VERSION 5.8 ;
BUSBITCHARS "[]" ;
DIVIDERCHAR "/" ;
UNITS
    DATABASE MICRONS 2000 ;
END UNITS

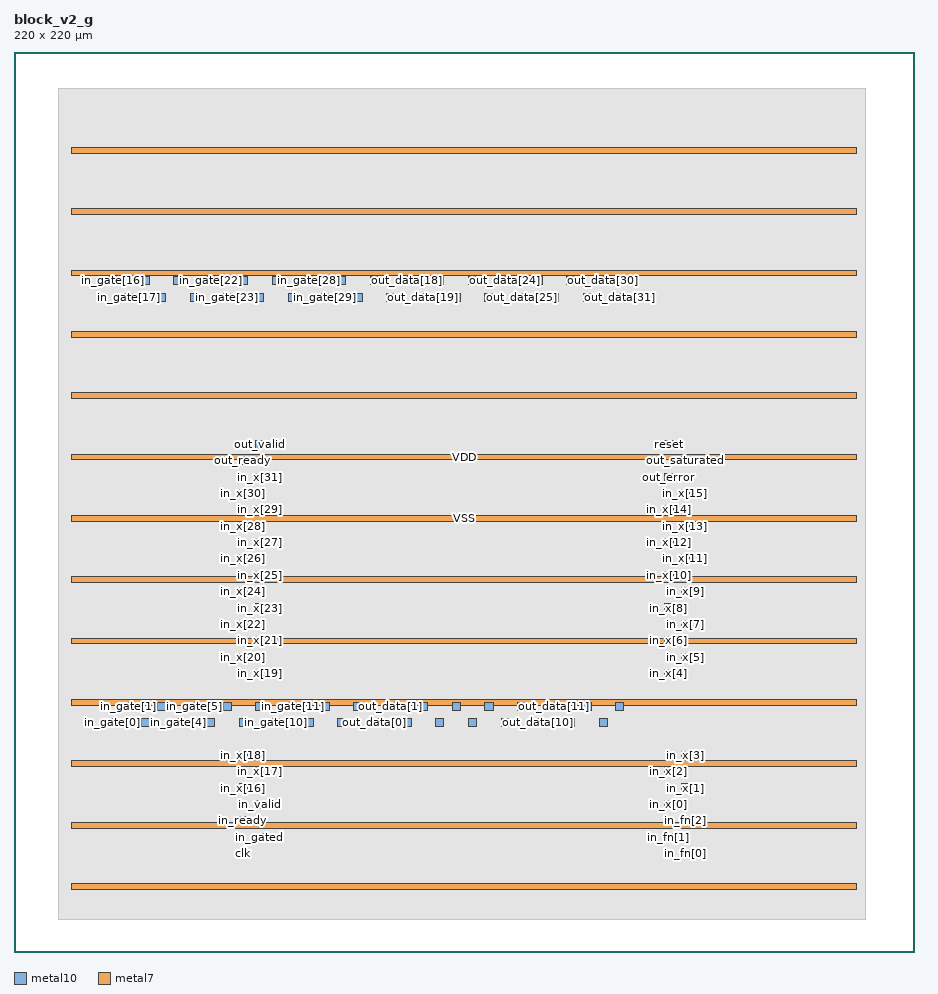
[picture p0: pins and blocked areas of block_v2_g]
MACRO block_v2_g
  FOREIGN block_v2_g 0 0 ;
  CLASS BLOCK ;
  SIZE 220 BY 220 ;
  PIN clk
    DIRECTION INPUT ;
    USE SIGNAL ;
    PORT
      LAYER metal10 ;
        RECT  55.095 23.07 57.095 25.07 ;
    END
  END clk
  PIN in_fn[0]
    DIRECTION INPUT ;
    USE SIGNAL ;
    PORT
      LAYER metal10 ;
        RECT  163.095 23.07 165.095 25.07 ;
    END
  END in_fn[0]
  PIN in_fn[1]
    DIRECTION INPUT ;
    USE SIGNAL ;
    PORT
      LAYER metal10 ;
        RECT  159.095 27.07 161.095 29.07 ;
    END
  END in_fn[1]
  PIN in_fn[2]
    DIRECTION INPUT ;
    USE SIGNAL ;
    PORT
      LAYER metal10 ;
        RECT  163.095 31.07 165.095 33.07 ;
    END
  END in_fn[2]
  PIN in_gate[0]
    DIRECTION INPUT ;
    USE SIGNAL ;
    PORT
      LAYER metal10 ;
        RECT  23.095 55.07 25.095 57.07 ;
    END
  END in_gate[0]
  PIN in_gate[10]
    DIRECTION INPUT ;
    USE SIGNAL ;
    PORT
      LAYER metal10 ;
        RECT  63.095 55.07 65.095 57.07 ;
    END
  END in_gate[10]
  PIN in_gate[11]
    DIRECTION INPUT ;
    USE SIGNAL ;
    PORT
      LAYER metal10 ;
        RECT  67.095 59.07 69.095 61.07 ;
    END
  END in_gate[11]
  PIN in_gate[12]
    DIRECTION INPUT ;
    USE SIGNAL ;
    PORT
      LAYER metal10 ;
        RECT  71.095 55.07 73.095 57.07 ;
    END
  END in_gate[12]
  PIN in_gate[13]
    DIRECTION INPUT ;
    USE SIGNAL ;
    PORT
      LAYER metal10 ;
        RECT  75.095 59.07 77.095 61.07 ;
    END
  END in_gate[13]
  PIN in_gate[14]
    DIRECTION INPUT ;
    USE SIGNAL ;
    PORT
      LAYER metal10 ;
        RECT  79.095 55.07 81.095 57.07 ;
    END
  END in_gate[14]
  PIN in_gate[15]
    DIRECTION INPUT ;
    USE SIGNAL ;
    PORT
      LAYER metal10 ;
        RECT  83.095 59.07 85.095 61.07 ;
    END
  END in_gate[15]
  PIN in_gate[16]
    DIRECTION INPUT ;
    USE SIGNAL ;
    PORT
      LAYER metal10 ;
        RECT  23.095 163.07 25.095 165.07 ;
    END
  END in_gate[16]
  PIN in_gate[17]
    DIRECTION INPUT ;
    USE SIGNAL ;
    PORT
      LAYER metal10 ;
        RECT  27.095 159.07 29.095 161.07 ;
    END
  END in_gate[17]
  PIN in_gate[18]
    DIRECTION INPUT ;
    USE SIGNAL ;
    PORT
      LAYER metal10 ;
        RECT  31.095 163.07 33.095 165.07 ;
    END
  END in_gate[18]
  PIN in_gate[19]
    DIRECTION INPUT ;
    USE SIGNAL ;
    PORT
      LAYER metal10 ;
        RECT  35.095 159.07 37.095 161.07 ;
    END
  END in_gate[19]
  PIN in_gate[1]
    DIRECTION INPUT ;
    USE SIGNAL ;
    PORT
      LAYER metal10 ;
        RECT  27.095 59.07 29.095 61.07 ;
    END
  END in_gate[1]
  PIN in_gate[20]
    DIRECTION INPUT ;
    USE SIGNAL ;
    PORT
      LAYER metal10 ;
        RECT  39.095 163.07 41.095 165.07 ;
    END
  END in_gate[20]
  PIN in_gate[21]
    DIRECTION INPUT ;
    USE SIGNAL ;
    PORT
      LAYER metal10 ;
        RECT  43.095 159.07 45.095 161.07 ;
    END
  END in_gate[21]
  PIN in_gate[22]
    DIRECTION INPUT ;
    USE SIGNAL ;
    PORT
      LAYER metal10 ;
        RECT  47.095 163.07 49.095 165.07 ;
    END
  END in_gate[22]
  PIN in_gate[23]
    DIRECTION INPUT ;
    USE SIGNAL ;
    PORT
      LAYER metal10 ;
        RECT  51.095 159.07 53.095 161.07 ;
    END
  END in_gate[23]
  PIN in_gate[24]
    DIRECTION INPUT ;
    USE SIGNAL ;
    PORT
      LAYER metal10 ;
        RECT  55.095 163.07 57.095 165.07 ;
    END
  END in_gate[24]
  PIN in_gate[25]
    DIRECTION INPUT ;
    USE SIGNAL ;
    PORT
      LAYER metal10 ;
        RECT  59.095 159.07 61.095 161.07 ;
    END
  END in_gate[25]
  PIN in_gate[26]
    DIRECTION INPUT ;
    USE SIGNAL ;
    PORT
      LAYER metal10 ;
        RECT  63.095 163.07 65.095 165.07 ;
    END
  END in_gate[26]
  PIN in_gate[27]
    DIRECTION INPUT ;
    USE SIGNAL ;
    PORT
      LAYER metal10 ;
        RECT  67.095 159.07 69.095 161.07 ;
    END
  END in_gate[27]
  PIN in_gate[28]
    DIRECTION INPUT ;
    USE SIGNAL ;
    PORT
      LAYER metal10 ;
        RECT  71.095 163.07 73.095 165.07 ;
    END
  END in_gate[28]
  PIN in_gate[29]
    DIRECTION INPUT ;
    USE SIGNAL ;
    PORT
      LAYER metal10 ;
        RECT  75.095 159.07 77.095 161.07 ;
    END
  END in_gate[29]
  PIN in_gate[2]
    DIRECTION INPUT ;
    USE SIGNAL ;
    PORT
      LAYER metal10 ;
        RECT  31.095 55.07 33.095 57.07 ;
    END
  END in_gate[2]
  PIN in_gate[30]
    DIRECTION INPUT ;
    USE SIGNAL ;
    PORT
      LAYER metal10 ;
        RECT  79.095 163.07 81.095 165.07 ;
    END
  END in_gate[30]
  PIN in_gate[31]
    DIRECTION INPUT ;
    USE SIGNAL ;
    PORT
      LAYER metal10 ;
        RECT  83.095 159.07 85.095 161.07 ;
    END
  END in_gate[31]
  PIN in_gate[3]
    DIRECTION INPUT ;
    USE SIGNAL ;
    PORT
      LAYER metal10 ;
        RECT  35.095 59.07 37.095 61.07 ;
    END
  END in_gate[3]
  PIN in_gate[4]
    DIRECTION INPUT ;
    USE SIGNAL ;
    PORT
      LAYER metal10 ;
        RECT  39.095 55.07 41.095 57.07 ;
    END
  END in_gate[4]
  PIN in_gate[5]
    DIRECTION INPUT ;
    USE SIGNAL ;
    PORT
      LAYER metal10 ;
        RECT  43.095 59.07 45.095 61.07 ;
    END
  END in_gate[5]
  PIN in_gate[6]
    DIRECTION INPUT ;
    USE SIGNAL ;
    PORT
      LAYER metal10 ;
        RECT  47.095 55.07 49.095 57.07 ;
    END
  END in_gate[6]
  PIN in_gate[7]
    DIRECTION INPUT ;
    USE SIGNAL ;
    PORT
      LAYER metal10 ;
        RECT  51.095 59.07 53.095 61.07 ;
    END
  END in_gate[7]
  PIN in_gate[8]
    DIRECTION INPUT ;
    USE SIGNAL ;
    PORT
      LAYER metal10 ;
        RECT  55.095 55.07 57.095 57.07 ;
    END
  END in_gate[8]
  PIN in_gate[9]
    DIRECTION INPUT ;
    USE SIGNAL ;
    PORT
      LAYER metal10 ;
        RECT  59.095 59.07 61.095 61.07 ;
    END
  END in_gate[9]
  PIN in_gated
    DIRECTION INPUT ;
    USE SIGNAL ;
    PORT
      LAYER metal10 ;
        RECT  59.095 27.07 61.095 29.07 ;
    END
  END in_gated
  PIN in_ready
    DIRECTION OUTPUT ;
    USE SIGNAL ;
    PORT
      LAYER metal10 ;
        RECT  55.095 31.07 57.095 33.07 ;
    END
  END in_ready
  PIN in_valid
    DIRECTION INPUT ;
    USE SIGNAL ;
    PORT
      LAYER metal10 ;
        RECT  59.095 35.07 61.095 37.07 ;
    END
  END in_valid
  PIN in_x[0]
    DIRECTION INPUT ;
    USE SIGNAL ;
    PORT
      LAYER metal10 ;
        RECT  159.095 35.07 161.095 37.07 ;
    END
  END in_x[0]
  PIN in_x[10]
    DIRECTION INPUT ;
    USE SIGNAL ;
    PORT
      LAYER metal10 ;
        RECT  159.095 91.07 161.095 93.07 ;
    END
  END in_x[10]
  PIN in_x[11]
    DIRECTION INPUT ;
    USE SIGNAL ;
    PORT
      LAYER metal10 ;
        RECT  163.095 95.07 165.095 97.07 ;
    END
  END in_x[11]
  PIN in_x[12]
    DIRECTION INPUT ;
    USE SIGNAL ;
    PORT
      LAYER metal10 ;
        RECT  159.095 99.07 161.095 101.07 ;
    END
  END in_x[12]
  PIN in_x[13]
    DIRECTION INPUT ;
    USE SIGNAL ;
    PORT
      LAYER metal10 ;
        RECT  163.095 103.07 165.095 105.07 ;
    END
  END in_x[13]
  PIN in_x[14]
    DIRECTION INPUT ;
    USE SIGNAL ;
    PORT
      LAYER metal10 ;
        RECT  159.095 107.07 161.095 109.07 ;
    END
  END in_x[14]
  PIN in_x[15]
    DIRECTION INPUT ;
    USE SIGNAL ;
    PORT
      LAYER metal10 ;
        RECT  163.095 111.07 165.095 113.07 ;
    END
  END in_x[15]
  PIN in_x[16]
    DIRECTION INPUT ;
    USE SIGNAL ;
    PORT
      LAYER metal10 ;
        RECT  55.095 39.07 57.095 41.07 ;
    END
  END in_x[16]
  PIN in_x[17]
    DIRECTION INPUT ;
    USE SIGNAL ;
    PORT
      LAYER metal10 ;
        RECT  59.095 43.07 61.095 45.07 ;
    END
  END in_x[17]
  PIN in_x[18]
    DIRECTION INPUT ;
    USE SIGNAL ;
    PORT
      LAYER metal10 ;
        RECT  55.095 47.07 57.095 49.07 ;
    END
  END in_x[18]
  PIN in_x[19]
    DIRECTION INPUT ;
    USE SIGNAL ;
    PORT
      LAYER metal10 ;
        RECT  59.095 67.07 61.095 69.07 ;
    END
  END in_x[19]
  PIN in_x[1]
    DIRECTION INPUT ;
    USE SIGNAL ;
    PORT
      LAYER metal10 ;
        RECT  163.095 39.07 165.095 41.07 ;
    END
  END in_x[1]
  PIN in_x[20]
    DIRECTION INPUT ;
    USE SIGNAL ;
    PORT
      LAYER metal10 ;
        RECT  55.095 71.07 57.095 73.07 ;
    END
  END in_x[20]
  PIN in_x[21]
    DIRECTION INPUT ;
    USE SIGNAL ;
    PORT
      LAYER metal10 ;
        RECT  59.095 75.07 61.095 77.07 ;
    END
  END in_x[21]
  PIN in_x[22]
    DIRECTION INPUT ;
    USE SIGNAL ;
    PORT
      LAYER metal10 ;
        RECT  55.095 79.07 57.095 81.07 ;
    END
  END in_x[22]
  PIN in_x[23]
    DIRECTION INPUT ;
    USE SIGNAL ;
    PORT
      LAYER metal10 ;
        RECT  59.095 83.07 61.095 85.07 ;
    END
  END in_x[23]
  PIN in_x[24]
    DIRECTION INPUT ;
    USE SIGNAL ;
    PORT
      LAYER metal10 ;
        RECT  55.095 87.07 57.095 89.07 ;
    END
  END in_x[24]
  PIN in_x[25]
    DIRECTION INPUT ;
    USE SIGNAL ;
    PORT
      LAYER metal10 ;
        RECT  59.095 91.07 61.095 93.07 ;
    END
  END in_x[25]
  PIN in_x[26]
    DIRECTION INPUT ;
    USE SIGNAL ;
    PORT
      LAYER metal10 ;
        RECT  55.095 95.07 57.095 97.07 ;
    END
  END in_x[26]
  PIN in_x[27]
    DIRECTION INPUT ;
    USE SIGNAL ;
    PORT
      LAYER metal10 ;
        RECT  59.095 99.07 61.095 101.07 ;
    END
  END in_x[27]
  PIN in_x[28]
    DIRECTION INPUT ;
    USE SIGNAL ;
    PORT
      LAYER metal10 ;
        RECT  55.095 103.07 57.095 105.07 ;
    END
  END in_x[28]
  PIN in_x[29]
    DIRECTION INPUT ;
    USE SIGNAL ;
    PORT
      LAYER metal10 ;
        RECT  59.095 107.07 61.095 109.07 ;
    END
  END in_x[29]
  PIN in_x[2]
    DIRECTION INPUT ;
    USE SIGNAL ;
    PORT
      LAYER metal10 ;
        RECT  159.095 43.07 161.095 45.07 ;
    END
  END in_x[2]
  PIN in_x[30]
    DIRECTION INPUT ;
    USE SIGNAL ;
    PORT
      LAYER metal10 ;
        RECT  55.095 111.07 57.095 113.07 ;
    END
  END in_x[30]
  PIN in_x[31]
    DIRECTION INPUT ;
    USE SIGNAL ;
    PORT
      LAYER metal10 ;
        RECT  59.095 115.07 61.095 117.07 ;
    END
  END in_x[31]
  PIN in_x[3]
    DIRECTION INPUT ;
    USE SIGNAL ;
    PORT
      LAYER metal10 ;
        RECT  163.095 47.07 165.095 49.07 ;
    END
  END in_x[3]
  PIN in_x[4]
    DIRECTION INPUT ;
    USE SIGNAL ;
    PORT
      LAYER metal10 ;
        RECT  159.095 67.07 161.095 69.07 ;
    END
  END in_x[4]
  PIN in_x[5]
    DIRECTION INPUT ;
    USE SIGNAL ;
    PORT
      LAYER metal10 ;
        RECT  163.095 71.07 165.095 73.07 ;
    END
  END in_x[5]
  PIN in_x[6]
    DIRECTION INPUT ;
    USE SIGNAL ;
    PORT
      LAYER metal10 ;
        RECT  159.095 75.07 161.095 77.07 ;
    END
  END in_x[6]
  PIN in_x[7]
    DIRECTION INPUT ;
    USE SIGNAL ;
    PORT
      LAYER metal10 ;
        RECT  163.095 79.07 165.095 81.07 ;
    END
  END in_x[7]
  PIN in_x[8]
    DIRECTION INPUT ;
    USE SIGNAL ;
    PORT
      LAYER metal10 ;
        RECT  159.095 83.07 161.095 85.07 ;
    END
  END in_x[8]
  PIN in_x[9]
    DIRECTION INPUT ;
    USE SIGNAL ;
    PORT
      LAYER metal10 ;
        RECT  163.095 87.07 165.095 89.07 ;
    END
  END in_x[9]
  PIN out_data[0]
    DIRECTION OUTPUT ;
    USE SIGNAL ;
    PORT
      LAYER metal10 ;
        RECT  87.095 55.07 89.095 57.07 ;
    END
  END out_data[0]
  PIN out_data[10]
    DIRECTION OUTPUT ;
    USE SIGNAL ;
    PORT
      LAYER metal10 ;
        RECT  127.095 55.07 129.095 57.07 ;
    END
  END out_data[10]
  PIN out_data[11]
    DIRECTION OUTPUT ;
    USE SIGNAL ;
    PORT
      LAYER metal10 ;
        RECT  131.095 59.07 133.095 61.07 ;
    END
  END out_data[11]
  PIN out_data[12]
    DIRECTION OUTPUT ;
    USE SIGNAL ;
    PORT
      LAYER metal10 ;
        RECT  135.095 55.07 137.095 57.07 ;
    END
  END out_data[12]
  PIN out_data[13]
    DIRECTION OUTPUT ;
    USE SIGNAL ;
    PORT
      LAYER metal10 ;
        RECT  139.095 59.07 141.095 61.07 ;
    END
  END out_data[13]
  PIN out_data[14]
    DIRECTION OUTPUT ;
    USE SIGNAL ;
    PORT
      LAYER metal10 ;
        RECT  143.095 55.07 145.095 57.07 ;
    END
  END out_data[14]
  PIN out_data[15]
    DIRECTION OUTPUT ;
    USE SIGNAL ;
    PORT
      LAYER metal10 ;
        RECT  147.095 59.07 149.095 61.07 ;
    END
  END out_data[15]
  PIN out_data[16]
    DIRECTION OUTPUT ;
    USE SIGNAL ;
    PORT
      LAYER metal10 ;
        RECT  87.095 163.07 89.095 165.07 ;
    END
  END out_data[16]
  PIN out_data[17]
    DIRECTION OUTPUT ;
    USE SIGNAL ;
    PORT
      LAYER metal10 ;
        RECT  91.095 159.07 93.095 161.07 ;
    END
  END out_data[17]
  PIN out_data[18]
    DIRECTION OUTPUT ;
    USE SIGNAL ;
    PORT
      LAYER metal10 ;
        RECT  95.095 163.07 97.095 165.07 ;
    END
  END out_data[18]
  PIN out_data[19]
    DIRECTION OUTPUT ;
    USE SIGNAL ;
    PORT
      LAYER metal10 ;
        RECT  99.095 159.07 101.095 161.07 ;
    END
  END out_data[19]
  PIN out_data[1]
    DIRECTION OUTPUT ;
    USE SIGNAL ;
    PORT
      LAYER metal10 ;
        RECT  91.095 59.07 93.095 61.07 ;
    END
  END out_data[1]
  PIN out_data[20]
    DIRECTION OUTPUT ;
    USE SIGNAL ;
    PORT
      LAYER metal10 ;
        RECT  103.095 163.07 105.095 165.07 ;
    END
  END out_data[20]
  PIN out_data[21]
    DIRECTION OUTPUT ;
    USE SIGNAL ;
    PORT
      LAYER metal10 ;
        RECT  107.095 159.07 109.095 161.07 ;
    END
  END out_data[21]
  PIN out_data[22]
    DIRECTION OUTPUT ;
    USE SIGNAL ;
    PORT
      LAYER metal10 ;
        RECT  111.095 163.07 113.095 165.07 ;
    END
  END out_data[22]
  PIN out_data[23]
    DIRECTION OUTPUT ;
    USE SIGNAL ;
    PORT
      LAYER metal10 ;
        RECT  115.095 159.07 117.095 161.07 ;
    END
  END out_data[23]
  PIN out_data[24]
    DIRECTION OUTPUT ;
    USE SIGNAL ;
    PORT
      LAYER metal10 ;
        RECT  119.095 163.07 121.095 165.07 ;
    END
  END out_data[24]
  PIN out_data[25]
    DIRECTION OUTPUT ;
    USE SIGNAL ;
    PORT
      LAYER metal10 ;
        RECT  123.095 159.07 125.095 161.07 ;
    END
  END out_data[25]
  PIN out_data[26]
    DIRECTION OUTPUT ;
    USE SIGNAL ;
    PORT
      LAYER metal10 ;
        RECT  127.095 163.07 129.095 165.07 ;
    END
  END out_data[26]
  PIN out_data[27]
    DIRECTION OUTPUT ;
    USE SIGNAL ;
    PORT
      LAYER metal10 ;
        RECT  131.095 159.07 133.095 161.07 ;
    END
  END out_data[27]
  PIN out_data[28]
    DIRECTION OUTPUT ;
    USE SIGNAL ;
    PORT
      LAYER metal10 ;
        RECT  135.095 163.07 137.095 165.07 ;
    END
  END out_data[28]
  PIN out_data[29]
    DIRECTION OUTPUT ;
    USE SIGNAL ;
    PORT
      LAYER metal10 ;
        RECT  139.095 159.07 141.095 161.07 ;
    END
  END out_data[29]
  PIN out_data[2]
    DIRECTION OUTPUT ;
    USE SIGNAL ;
    PORT
      LAYER metal10 ;
        RECT  95.095 55.07 97.095 57.07 ;
    END
  END out_data[2]
  PIN out_data[30]
    DIRECTION OUTPUT ;
    USE SIGNAL ;
    PORT
      LAYER metal10 ;
        RECT  143.095 163.07 145.095 165.07 ;
    END
  END out_data[30]
  PIN out_data[31]
    DIRECTION OUTPUT ;
    USE SIGNAL ;
    PORT
      LAYER metal10 ;
        RECT  147.095 159.07 149.095 161.07 ;
    END
  END out_data[31]
  PIN out_data[3]
    DIRECTION OUTPUT ;
    USE SIGNAL ;
    PORT
      LAYER metal10 ;
        RECT  99.095 59.07 101.095 61.07 ;
    END
  END out_data[3]
  PIN out_data[4]
    DIRECTION OUTPUT ;
    USE SIGNAL ;
    PORT
      LAYER metal10 ;
        RECT  103.095 55.07 105.095 57.07 ;
    END
  END out_data[4]
  PIN out_data[5]
    DIRECTION OUTPUT ;
    USE SIGNAL ;
    PORT
      LAYER metal10 ;
        RECT  107.095 59.07 109.095 61.07 ;
    END
  END out_data[5]
  PIN out_data[6]
    DIRECTION OUTPUT ;
    USE SIGNAL ;
    PORT
      LAYER metal10 ;
        RECT  111.095 55.07 113.095 57.07 ;
    END
  END out_data[6]
  PIN out_data[7]
    DIRECTION OUTPUT ;
    USE SIGNAL ;
    PORT
      LAYER metal10 ;
        RECT  115.095 59.07 117.095 61.07 ;
    END
  END out_data[7]
  PIN out_data[8]
    DIRECTION OUTPUT ;
    USE SIGNAL ;
    PORT
      LAYER metal10 ;
        RECT  119.095 55.07 121.095 57.07 ;
    END
  END out_data[8]
  PIN out_data[9]
    DIRECTION OUTPUT ;
    USE SIGNAL ;
    PORT
      LAYER metal10 ;
        RECT  123.095 59.07 125.095 61.07 ;
    END
  END out_data[9]
  PIN out_error
    DIRECTION OUTPUT ;
    USE SIGNAL ;
    PORT
      LAYER metal10 ;
        RECT  159.095 115.07 161.095 117.07 ;
    END
  END out_error
  PIN out_ready
    DIRECTION INPUT ;
    USE SIGNAL ;
    PORT
      LAYER metal10 ;
        RECT  55.095 119.07 57.095 121.07 ;
    END
  END out_ready
  PIN out_saturated
    DIRECTION OUTPUT ;
    USE SIGNAL ;
    PORT
      LAYER metal10 ;
        RECT  163.095 119.07 165.095 121.07 ;
    END
  END out_saturated
  PIN out_valid
    DIRECTION OUTPUT ;
    USE SIGNAL ;
    PORT
      LAYER metal10 ;
        RECT  59.095 123.07 61.095 125.07 ;
    END
  END out_valid
  PIN reset
    DIRECTION INPUT ;
    USE SIGNAL ;
    PORT
      LAYER metal10 ;
        RECT  159.095 123.07 161.095 125.07 ;
    END
  END reset
  PIN VSS
    DIRECTION INOUT ;
    USE GROUND ;
    PORT
      LAYER metal7 ;
        RECT  14.06 195.3 205.96 196.7 ;
        RECT  14.06 165.3 205.96 166.7 ;
        RECT  14.06 135.3 205.96 136.7 ;
        RECT  14.06 105.3 205.96 106.7 ;
        RECT  14.06 75.3 205.96 76.7 ;
        RECT  14.06 45.3 205.96 46.7 ;
        RECT  14.06 15.3 205.96 16.7 ;
    END
  END VSS
  PIN VDD
    DIRECTION INOUT ;
    USE POWER ;
    PORT
      LAYER metal7 ;
        RECT  14.06 180.3 205.96 181.7 ;
        RECT  14.06 150.3 205.96 151.7 ;
        RECT  14.06 120.3 205.96 121.7 ;
        RECT  14.06 90.3 205.96 91.7 ;
        RECT  14.06 60.3 205.96 61.7 ;
        RECT  14.06 30.3 205.96 31.7 ;
    END
  END VDD
  OBS
    LAYER metal1 ;
     RECT  10.945 7.84 208.205 210.98 ;
    LAYER metal2 ;
     RECT  10.945 7.84 208.205 210.98 ;
    LAYER metal3 ;
     RECT  10.945 7.84 208.205 210.98 ;
    LAYER metal4 ;
     RECT  10.945 7.84 208.205 210.98 ;
    LAYER metal5 ;
     RECT  10.945 7.84 208.205 210.98 ;
    LAYER metal6 ;
     RECT  10.945 7.84 208.205 210.98 ;
    LAYER metal7 ;
     RECT  10.945 7.84 208.205 210.98 ;
    LAYER metal8 ;
     RECT  10.945 7.84 208.205 210.98 ;
    LAYER metal9 ;
     RECT  10.945 7.84 208.205 210.98 ;
    LAYER metal10 ;
     RECT  10.945 7.84 208.205 210.98 ;
  END
END block_v2_g
END LIBRARY
